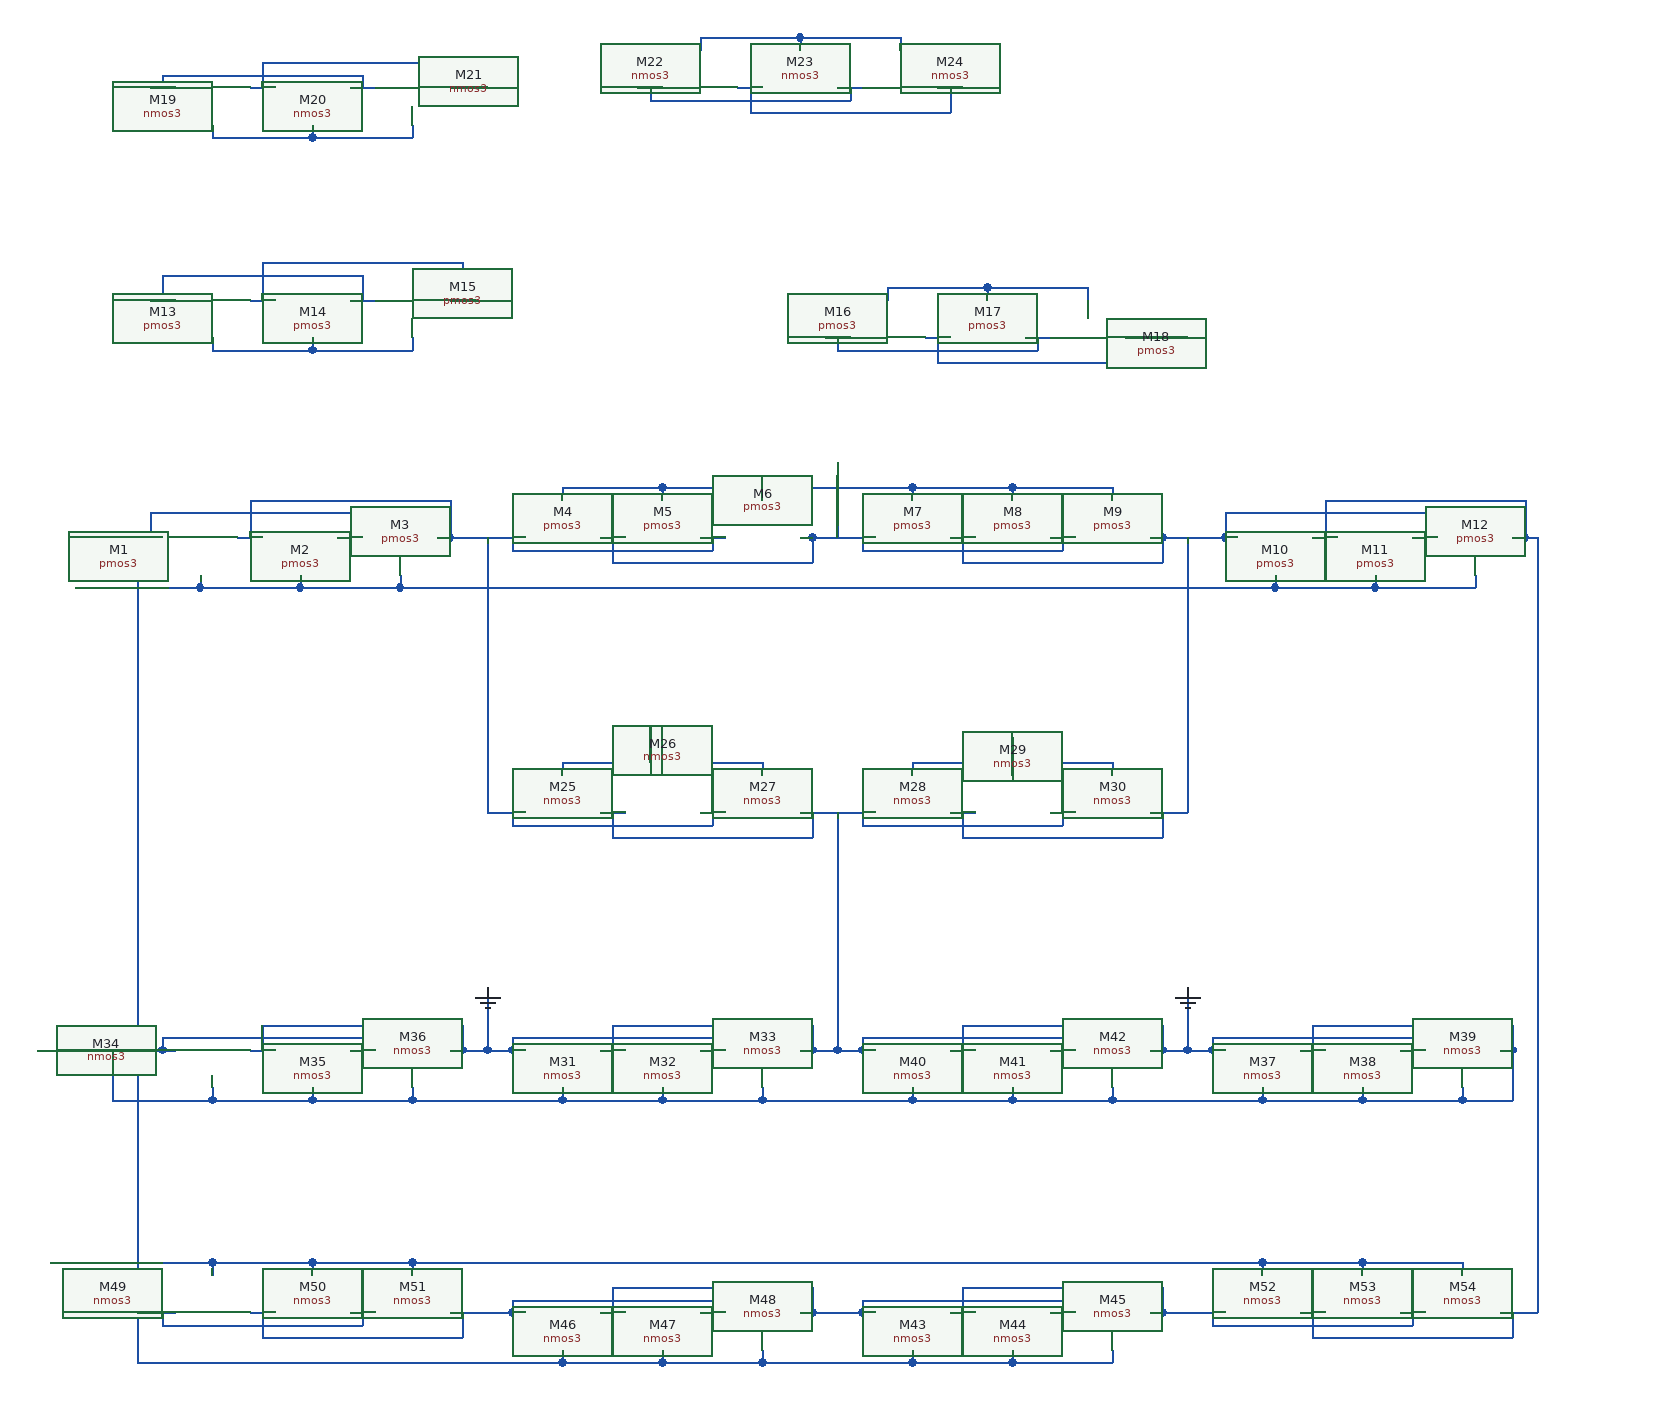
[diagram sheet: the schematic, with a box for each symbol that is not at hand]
v {xschem version=3.4.3 file_version=1.2
}
G {}
K {}
V {}
S {}
E {}
N 230 -50 230 -40 {
lab=#net1}
N 230 -40 310 -40 {
lab=#net1}
N 310 -50 310 -40 {
lab=#net1}
N 310 -40 390 -40 {
lab=#net1}
N 390 -50 390 -40 {
lab=#net1}
N 260 -80 280 -80 {
lab=#net2}
N 340 -80 360 -80 {
lab=#net3}
N 190 -80 200 -80 {
lab=#net3}
N 190 -100 190 -80 {
lab=#net3}
N 190 -100 350 -100 {
lab=#net3}
N 350 -100 350 -80 {
lab=#net3}
N 420 -80 430 -80 {
lab=#net2}
N 180 -80 190 -80 {
lab=#net3}
N 270 -110 270 -80 {
lab=#net2}
N 270 -110 420 -110 {
lab=#net2}
N 420 -110 430 -110 {
lab=#net2}
N 430 -110 430 -80 {
lab=#net2}
N 430 -80 440 -80 {
lab=#net2}
N 520 -120 520 -110 {
lab=#net4}
N 520 -120 600 -120 {
lab=#net4}
N 600 -120 600 -110 {
lab=#net4}
N 600 -120 680 -120 {
lab=#net4}
N 680 -120 680 -110 {
lab=#net4}
N 550 -80 570 -80 {
lab=#net5}
N 630 -80 650 -80 {
lab=#net2}
N 710 -80 720 -80 {
lab=#net5}
N 720 -80 730 -80 {
lab=#net5}
N 470 -80 490 -80 {
lab=#net2}
N 480 -80 480 -70 {
lab=#net2}
N 480 -70 640 -70 {
lab=#net2}
N 640 -80 640 -70 {
lab=#net2}
N 720 -80 720 -60 {
lab=#net5}
N 560 -60 720 -60 {
lab=#net5}
N 560 -80 560 -60 {
lab=#net5}
N 800 -120 800 -110 {
lab=#net4}
N 800 -120 880 -120 {
lab=#net4}
N 880 -120 880 -110 {
lab=#net4}
N 880 -120 960 -120 {
lab=#net4}
N 960 -120 960 -110 {
lab=#net4}
N 830 -80 850 -80 {
lab=#net6}
N 910 -80 930 -80 {
lab=#net5}
N 990 -80 1000 -80 {
lab=#net6}
N 1000 -80 1010 -80 {
lab=#net6}
N 750 -80 770 -80 {
lab=#net5}
N 760 -80 760 -70 {
lab=#net5}
N 760 -70 920 -70 {
lab=#net5}
N 920 -80 920 -70 {
lab=#net5}
N 1000 -80 1000 -60 {
lab=#net6}
N 840 -60 1000 -60 {
lab=#net6}
N 840 -80 840 -60 {
lab=#net6}
N 1090 -50 1090 -40 {
lab=#net1}
N 1090 -40 1170 -40 {
lab=#net1}
N 1170 -50 1170 -40 {
lab=#net1}
N 1170 -40 1250 -40 {
lab=#net1}
N 1250 -50 1250 -40 {
lab=#net1}
N 1120 -80 1140 -80 {
lab=#net7}
N 1200 -80 1220 -80 {
lab=#net6}
N 1050 -80 1060 -80 {
lab=#net6}
N 1050 -100 1050 -80 {
lab=#net6}
N 1050 -100 1210 -100 {
lab=#net6}
N 1210 -100 1210 -80 {
lab=#net6}
N 1280 -80 1290 -80 {
lab=#net7}
N 1040 -80 1050 -80 {
lab=#net6}
N 1130 -110 1130 -80 {
lab=#net7}
N 1130 -110 1280 -110 {
lab=#net7}
N 1280 -110 1290 -110 {
lab=#net7}
N 1290 -110 1290 -80 {
lab=#net7}
N 1290 -80 1300 -80 {
lab=#net7}
N 440 -80 470 -80 {
lab=#net2}
N 730 -80 750 -80 {
lab=#net5}
N 740 -140 740 -80 {
lab=#net5}
N 1010 -80 1040 -80 {
lab=#net6}
N 390 -40 1090 -40 {
lab=#net1}
N 680 -120 800 -120 {
lab=#net4}
N 240 -240 240 -230 {
lab=#net8}
N 240 -230 320 -230 {
lab=#net8}
N 320 -240 320 -230 {
lab=#net8}
N 320 -230 400 -230 {
lab=#net8}
N 400 -240 400 -230 {
lab=#net8}
N 270 -270 290 -270 {
lab=#net9}
N 350 -270 370 -270 {
lab=#net10}
N 200 -270 210 -270 {
lab=#net10}
N 200 -290 200 -270 {
lab=#net10}
N 200 -290 360 -290 {
lab=#net10}
N 360 -290 360 -270 {
lab=#net10}
N 430 -270 440 -270 {
lab=#net9}
N 190 -270 200 -270 {
lab=#net10}
N 280 -300 280 -270 {
lab=#net9}
N 280 -300 430 -300 {
lab=#net9}
N 430 -300 440 -300 {
lab=#net9}
N 440 -300 440 -270 {
lab=#net9}
N 440 -270 450 -270 {
lab=#net9}
N 780 -280 780 -270 {
lab=#net11}
N 780 -280 860 -280 {
lab=#net11}
N 860 -280 860 -270 {
lab=#net11}
N 860 -280 940 -280 {
lab=#net11}
N 940 -280 940 -270 {
lab=#net11}
N 810 -240 830 -240 {
lab=#net12}
N 890 -240 910 -240 {
lab=#net13}
N 970 -240 980 -240 {
lab=#net12}
N 980 -240 990 -240 {
lab=#net12}
N 730 -240 750 -240 {
lab=#net13}
N 740 -240 740 -230 {
lab=#net13}
N 740 -230 900 -230 {
lab=#net13}
N 900 -240 900 -230 {
lab=#net13}
N 980 -240 980 -220 {
lab=#net12}
N 820 -220 980 -220 {
lab=#net12}
N 820 -240 820 -220 {
lab=#net12}
N 990 -240 1020 -240 {
lab=#net12}
N 130 -40 230 -40 {
lab=#net1}
N 240 -410 240 -400 {
lab=#net14}
N 240 -400 320 -400 {
lab=#net14}
N 320 -410 320 -400 {
lab=#net14}
N 320 -400 400 -400 {
lab=#net14}
N 400 -410 400 -400 {
lab=#net14}
N 200 -440 210 -440 {
lab=#net15}
N 270 -440 290 -440 {
lab=#net16}
N 350 -440 370 -440 {
lab=#net15}
N 430 -440 440 -440 {
lab=#net16}
N 440 -440 460 -440 {
lab=#net16}
N 190 -440 200 -440 {
lab=#net15}
N 360 -450 360 -440 {
lab=#net15}
N 200 -450 360 -450 {
lab=#net15}
N 200 -450 200 -440 {
lab=#net15}
N 280 -460 280 -440 {
lab=#net16}
N 280 -460 440 -460 {
lab=#net16}
N 440 -460 440 -440 {
lab=#net16}
N 660 -440 680 -440 {
lab=#net17}
N 740 -440 760 -440 {
lab=#net18}
N 630 -480 630 -470 {
lab=#net19}
N 630 -480 710 -480 {
lab=#net19}
N 710 -480 710 -470 {
lab=#net19}
N 710 -480 790 -480 {
lab=#net19}
N 790 -480 790 -470 {
lab=#net19}
N 580 -440 600 -440 {
lab=#net18}
N 820 -440 840 -440 {
lab=#net17}
N 590 -440 590 -430 {
lab=#net18}
N 590 -430 750 -430 {
lab=#net18}
N 750 -440 750 -430 {
lab=#net18}
N 670 -440 670 -420 {
lab=#net17}
N 670 -420 830 -420 {
lab=#net17}
N 830 -440 830 -420 {
lab=#net17}
N 830 140 850 140 {
lab=#net6}
N 910 140 930 140 {
lab=#net20}
N 800 100 800 110 {
lab=#net21}
N 800 100 880 100 {
lab=#net21}
N 880 100 880 110 {
lab=#net21}
N 880 100 960 100 {
lab=#net21}
N 960 100 960 110 {
lab=#net21}
N 750 140 770 140 {
lab=#net20}
N 990 140 1010 140 {
lab=#net6}
N 760 140 760 150 {
lab=#net20}
N 760 150 920 150 {
lab=#net20}
N 920 140 920 150 {
lab=#net20}
N 840 140 840 160 {
lab=#net6}
N 840 160 1000 160 {
lab=#net6}
N 1000 140 1000 160 {
lab=#net6}
N 550 140 570 140 {
lab=#net20}
N 630 140 650 140 {
lab=#net2}
N 520 100 520 110 {
lab=#net22}
N 520 100 600 100 {
lab=#net22}
N 600 100 600 110 {
lab=#net22}
N 600 100 680 100 {
lab=#net22}
N 680 100 680 110 {
lab=#net22}
N 470 140 490 140 {
lab=#net2}
N 710 140 730 140 {
lab=#net20}
N 480 140 480 150 {
lab=#net2}
N 480 150 640 150 {
lab=#net2}
N 640 140 640 150 {
lab=#net2}
N 560 140 560 160 {
lab=#net20}
N 560 160 720 160 {
lab=#net20}
N 720 140 720 160 {
lab=#net20}
N 460 -80 460 140 {
lab=#net2}
N 1010 140 1020 140 {
lab=#net6}
N 1020 -80 1020 140 {
lab=#net6}
N 590 70 590 100 {
lab=#net22}
N 880 80 880 90 {
lab=#net21}
N 880 90 880 100 {
lab=#net21}
N 730 140 750 140 {
lab=#net20}
N 740 140 740 240 {
lab=#net20}
N 460 140 470 140 {
lab=#net2}
N 520 360 520 370 {
lab=#net23}
N 520 370 600 370 {
lab=#net23}
N 600 360 600 370 {
lab=#net23}
N 600 370 680 370 {
lab=#net23}
N 680 360 680 370 {
lab=#net23}
N 480 330 490 330 {
lab=GND}
N 550 330 570 330 {
lab=#net20}
N 630 330 650 330 {
lab=GND}
N 710 330 720 330 {
lab=#net20}
N 720 330 740 330 {
lab=#net20}
N 470 330 480 330 {
lab=GND}
N 640 320 640 330 {
lab=GND}
N 480 320 640 320 {
lab=GND}
N 480 320 480 330 {
lab=GND}
N 560 310 560 330 {
lab=#net20}
N 560 310 720 310 {
lab=#net20}
N 720 310 720 330 {
lab=#net20}
N 240 360 240 370 {
lab=#net23}
N 240 370 320 370 {
lab=#net23}
N 320 360 320 370 {
lab=#net23}
N 320 370 400 370 {
lab=#net23}
N 400 360 400 370 {
lab=#net23}
N 200 330 210 330 {
lab=#net23}
N 270 330 290 330 {
lab=GND}
N 350 330 370 330 {
lab=#net23}
N 430 330 440 330 {
lab=GND}
N 440 330 460 330 {
lab=GND}
N 190 330 200 330 {
lab=#net23}
N 360 320 360 330 {
lab=#net23}
N 200 320 360 320 {
lab=#net23}
N 200 320 200 330 {
lab=#net23}
N 280 310 280 330 {
lab=GND}
N 280 310 440 310 {
lab=GND}
N 440 310 440 330 {
lab=GND}
N 400 370 520 370 {
lab=#net23}
N 460 330 470 330 {
lab=GND}
N 460 280 460 330 {
lab=GND}
N 740 240 740 330 {
lab=#net20}
N 1080 360 1080 370 {
lab=#net23}
N 1080 370 1160 370 {
lab=#net23}
N 1160 360 1160 370 {
lab=#net23}
N 1160 370 1240 370 {
lab=#net23}
N 1240 360 1240 370 {
lab=#net23}
N 1040 330 1050 330 {
lab=GND}
N 1110 330 1130 330 {
lab=#net23}
N 1190 330 1210 330 {
lab=GND}
N 1270 330 1280 330 {
lab=#net23}
N 1030 330 1040 330 {
lab=GND}
N 1200 320 1200 330 {
lab=GND}
N 1040 320 1200 320 {
lab=GND}
N 1040 320 1040 330 {
lab=GND}
N 1120 310 1120 330 {
lab=#net23}
N 1120 310 1280 310 {
lab=#net23}
N 1280 310 1280 330 {
lab=#net23}
N 800 360 800 370 {
lab=#net23}
N 800 370 880 370 {
lab=#net23}
N 880 360 880 370 {
lab=#net23}
N 880 370 960 370 {
lab=#net23}
N 960 360 960 370 {
lab=#net23}
N 760 330 770 330 {
lab=#net20}
N 830 330 850 330 {
lab=GND}
N 910 330 930 330 {
lab=#net20}
N 990 330 1000 330 {
lab=GND}
N 1000 330 1020 330 {
lab=GND}
N 750 330 760 330 {
lab=#net20}
N 920 320 920 330 {
lab=#net20}
N 760 320 920 320 {
lab=#net20}
N 760 320 760 330 {
lab=#net20}
N 840 310 840 330 {
lab=GND}
N 840 310 1000 310 {
lab=GND}
N 1000 310 1000 330 {
lab=GND}
N 960 370 1080 370 {
lab=#net23}
N 1020 330 1030 330 {
lab=GND}
N 1020 280 1020 330 {
lab=GND}
N 740 330 750 330 {
lab=#net20}
N 100 330 190 330 {
lab=#net23}
N 160 370 240 370 {
lab=#net23}
N 160 330 160 370 {
lab=#net23}
N 680 370 800 370 {
lab=#net23}
N 1240 370 1280 370 {
lab=#net23}
N 1280 330 1280 370 {
lab=#net23}
N 800 570 800 580 {
lab=#net3}
N 800 580 880 580 {
lab=#net3}
N 880 570 880 580 {
lab=#net3}
N 880 580 960 580 {
lab=#net3}
N 960 570 960 580 {
lab=#net3}
N 760 540 770 540 {
lab=#net24}
N 830 540 850 540 {
lab=#net25}
N 910 540 930 540 {
lab=#net24}
N 990 540 1000 540 {
lab=#net25}
N 1000 540 1020 540 {
lab=#net25}
N 750 540 760 540 {
lab=#net24}
N 920 530 920 540 {
lab=#net24}
N 760 530 920 530 {
lab=#net24}
N 760 530 760 540 {
lab=#net24}
N 840 520 840 540 {
lab=#net25}
N 840 520 1000 520 {
lab=#net25}
N 1000 520 1000 540 {
lab=#net25}
N 520 570 520 580 {
lab=#net3}
N 520 580 600 580 {
lab=#net3}
N 600 570 600 580 {
lab=#net3}
N 600 580 680 580 {
lab=#net3}
N 680 570 680 580 {
lab=#net3}
N 480 540 490 540 {
lab=#net26}
N 550 540 570 540 {
lab=#net24}
N 630 540 650 540 {
lab=#net26}
N 710 540 720 540 {
lab=#net24}
N 720 540 740 540 {
lab=#net24}
N 470 540 480 540 {
lab=#net26}
N 640 530 640 540 {
lab=#net26}
N 480 530 640 530 {
lab=#net26}
N 480 530 480 540 {
lab=#net26}
N 560 520 560 540 {
lab=#net24}
N 560 520 720 520 {
lab=#net24}
N 720 520 720 540 {
lab=#net24}
N 740 540 750 540 {
lab=#net24}
N 270 540 290 540 {
lab=#net26}
N 350 540 370 540 {
lab=#net3}
N 240 500 240 510 {
lab=#net27}
N 240 500 320 500 {
lab=#net27}
N 320 500 320 510 {
lab=#net27}
N 320 500 400 500 {
lab=#net27}
N 400 500 400 510 {
lab=#net27}
N 190 540 210 540 {
lab=#net3}
N 430 540 450 540 {
lab=#net26}
N 200 540 200 550 {
lab=#net3}
N 200 550 360 550 {
lab=#net3}
N 360 540 360 550 {
lab=#net3}
N 280 540 280 560 {
lab=#net26}
N 280 560 440 560 {
lab=#net26}
N 440 540 440 560 {
lab=#net26}
N 1110 540 1130 540 {
lab=#net7}
N 1190 540 1210 540 {
lab=#net25}
N 1080 500 1080 510 {
lab=#net27}
N 1080 500 1160 500 {
lab=#net27}
N 1160 500 1160 510 {
lab=#net27}
N 1160 500 1240 500 {
lab=#net27}
N 1240 500 1240 510 {
lab=#net27}
N 1030 540 1050 540 {
lab=#net25}
N 1270 540 1290 540 {
lab=#net7}
N 1040 540 1040 550 {
lab=#net25}
N 1040 550 1200 550 {
lab=#net25}
N 1200 540 1200 550 {
lab=#net25}
N 1120 540 1120 560 {
lab=#net7}
N 1120 560 1280 560 {
lab=#net7}
N 1280 540 1280 560 {
lab=#net7}
N 1020 540 1030 540 {
lab=#net25}
N 450 540 470 540 {
lab=#net26}
N 400 500 1080 500 {
lab=#net27}
N 110 500 240 500 {
lab=#net27}
N 680 580 800 580 {
lab=#net3}
N 180 580 520 580 {
lab=#net3}
N 180 -80 180 580 {
lab=#net3}
N 180 540 190 540 {
lab=#net3}
N 1290 540 1300 540 {
lab=#net7}
N 1300 -80 1300 540 {
lab=#net7}
C {madvlsi/pmos3.sym} 230 -80 3 0 {name=M1
L=0.5
W=4
body=VDD
nf=1
mult=1
ad="'int((nf+1)/2) * W/nf * 0.29'" 
pd="'2*int((nf+1)/2) * (W/nf + 0.29)'"
as="'int((nf+2)/2) * W/nf * 0.29'" 
ps="'2*int((nf+2)/2) * (W/nf + 0.29)'"
nrd="'0.29 / W'" nrs="'0.29 / W'"
sa=0 sb=0 sd=0
model=pfet_01v8
spiceprefix=X
}
C {madvlsi/pmos3.sym} 310 -80 3 0 {name=M2
L=0.5
W=4
body=VDD
nf=1
mult=1
ad="'int((nf+1)/2) * W/nf * 0.29'" 
pd="'2*int((nf+1)/2) * (W/nf + 0.29)'"
as="'int((nf+2)/2) * W/nf * 0.29'" 
ps="'2*int((nf+2)/2) * (W/nf + 0.29)'"
nrd="'0.29 / W'" nrs="'0.29 / W'"
sa=0 sb=0 sd=0
model=pfet_01v8
spiceprefix=X
}
C {madvlsi/pmos3.sym} 390 -80 3 0 {name=M3
L=0.5
W=4
body=VDD
nf=1
mult=1
ad="'int((nf+1)/2) * W/nf * 0.29'" 
pd="'2*int((nf+1)/2) * (W/nf + 0.29)'"
as="'int((nf+2)/2) * W/nf * 0.29'" 
ps="'2*int((nf+2)/2) * (W/nf + 0.29)'"
nrd="'0.29 / W'" nrs="'0.29 / W'"
sa=0 sb=0 sd=0
model=pfet_01v8
spiceprefix=X
}
C {madvlsi/pmos3.sym} 520 -80 1 0 {name=M4
L=0.5
W=4
body=VDD
nf=1
mult=1
ad="'int((nf+1)/2) * W/nf * 0.29'" 
pd="'2*int((nf+1)/2) * (W/nf + 0.29)'"
as="'int((nf+2)/2) * W/nf * 0.29'" 
ps="'2*int((nf+2)/2) * (W/nf + 0.29)'"
nrd="'0.29 / W'" nrs="'0.29 / W'"
sa=0 sb=0 sd=0
model=pfet_01v8
spiceprefix=X
}
C {madvlsi/pmos3.sym} 600 -80 1 0 {name=M5
L=0.5
W=4
body=VDD
nf=1
mult=1
ad="'int((nf+1)/2) * W/nf * 0.29'" 
pd="'2*int((nf+1)/2) * (W/nf + 0.29)'"
as="'int((nf+2)/2) * W/nf * 0.29'" 
ps="'2*int((nf+2)/2) * (W/nf + 0.29)'"
nrd="'0.29 / W'" nrs="'0.29 / W'"
sa=0 sb=0 sd=0
model=pfet_01v8
spiceprefix=X
}
C {madvlsi/pmos3.sym} 680 -80 1 0 {name=M6
L=0.5
W=4
body=VDD
nf=1
mult=1
ad="'int((nf+1)/2) * W/nf * 0.29'" 
pd="'2*int((nf+1)/2) * (W/nf + 0.29)'"
as="'int((nf+2)/2) * W/nf * 0.29'" 
ps="'2*int((nf+2)/2) * (W/nf + 0.29)'"
nrd="'0.29 / W'" nrs="'0.29 / W'"
sa=0 sb=0 sd=0
model=pfet_01v8
spiceprefix=X
}
C {madvlsi/pmos3.sym} 800 -80 1 0 {name=M7
L=0.5
W=4
body=VDD
nf=1
mult=1
ad="'int((nf+1)/2) * W/nf * 0.29'" 
pd="'2*int((nf+1)/2) * (W/nf + 0.29)'"
as="'int((nf+2)/2) * W/nf * 0.29'" 
ps="'2*int((nf+2)/2) * (W/nf + 0.29)'"
nrd="'0.29 / W'" nrs="'0.29 / W'"
sa=0 sb=0 sd=0
model=pfet_01v8
spiceprefix=X
}
C {madvlsi/pmos3.sym} 880 -80 1 0 {name=M8
L=0.5
W=4
body=VDD
nf=1
mult=1
ad="'int((nf+1)/2) * W/nf * 0.29'" 
pd="'2*int((nf+1)/2) * (W/nf + 0.29)'"
as="'int((nf+2)/2) * W/nf * 0.29'" 
ps="'2*int((nf+2)/2) * (W/nf + 0.29)'"
nrd="'0.29 / W'" nrs="'0.29 / W'"
sa=0 sb=0 sd=0
model=pfet_01v8
spiceprefix=X
}
C {madvlsi/pmos3.sym} 960 -80 1 0 {name=M9
L=0.5
W=4
body=VDD
nf=1
mult=1
ad="'int((nf+1)/2) * W/nf * 0.29'" 
pd="'2*int((nf+1)/2) * (W/nf + 0.29)'"
as="'int((nf+2)/2) * W/nf * 0.29'" 
ps="'2*int((nf+2)/2) * (W/nf + 0.29)'"
nrd="'0.29 / W'" nrs="'0.29 / W'"
sa=0 sb=0 sd=0
model=pfet_01v8
spiceprefix=X
}
C {madvlsi/pmos3.sym} 1090 -80 3 0 {name=M10
L=0.5
W=4
body=VDD
nf=1
mult=1
ad="'int((nf+1)/2) * W/nf * 0.29'" 
pd="'2*int((nf+1)/2) * (W/nf + 0.29)'"
as="'int((nf+2)/2) * W/nf * 0.29'" 
ps="'2*int((nf+2)/2) * (W/nf + 0.29)'"
nrd="'0.29 / W'" nrs="'0.29 / W'"
sa=0 sb=0 sd=0
model=pfet_01v8
spiceprefix=X
}
C {madvlsi/pmos3.sym} 1170 -80 3 0 {name=M11
L=0.5
W=4
body=VDD
nf=1
mult=1
ad="'int((nf+1)/2) * W/nf * 0.29'" 
pd="'2*int((nf+1)/2) * (W/nf + 0.29)'"
as="'int((nf+2)/2) * W/nf * 0.29'" 
ps="'2*int((nf+2)/2) * (W/nf + 0.29)'"
nrd="'0.29 / W'" nrs="'0.29 / W'"
sa=0 sb=0 sd=0
model=pfet_01v8
spiceprefix=X
}
C {madvlsi/pmos3.sym} 1250 -80 3 0 {name=M12
L=0.5
W=4
body=VDD
nf=1
mult=1
ad="'int((nf+1)/2) * W/nf * 0.29'" 
pd="'2*int((nf+1)/2) * (W/nf + 0.29)'"
as="'int((nf+2)/2) * W/nf * 0.29'" 
ps="'2*int((nf+2)/2) * (W/nf + 0.29)'"
nrd="'0.29 / W'" nrs="'0.29 / W'"
sa=0 sb=0 sd=0
model=pfet_01v8
spiceprefix=X
}
C {madvlsi/pmos3.sym} 240 -270 3 0 {name=M13
L=0.5
W=4
body=VDD
nf=1
mult=1
ad="'int((nf+1)/2) * W/nf * 0.29'" 
pd="'2*int((nf+1)/2) * (W/nf + 0.29)'"
as="'int((nf+2)/2) * W/nf * 0.29'" 
ps="'2*int((nf+2)/2) * (W/nf + 0.29)'"
nrd="'0.29 / W'" nrs="'0.29 / W'"
sa=0 sb=0 sd=0
model=pfet_01v8
spiceprefix=X
}
C {madvlsi/pmos3.sym} 320 -270 3 0 {name=M14
L=0.5
W=4
body=VDD
nf=1
mult=1
ad="'int((nf+1)/2) * W/nf * 0.29'" 
pd="'2*int((nf+1)/2) * (W/nf + 0.29)'"
as="'int((nf+2)/2) * W/nf * 0.29'" 
ps="'2*int((nf+2)/2) * (W/nf + 0.29)'"
nrd="'0.29 / W'" nrs="'0.29 / W'"
sa=0 sb=0 sd=0
model=pfet_01v8
spiceprefix=X
}
C {madvlsi/pmos3.sym} 400 -270 3 0 {name=M15
L=0.5
W=4
body=VDD
nf=1
mult=1
ad="'int((nf+1)/2) * W/nf * 0.29'" 
pd="'2*int((nf+1)/2) * (W/nf + 0.29)'"
as="'int((nf+2)/2) * W/nf * 0.29'" 
ps="'2*int((nf+2)/2) * (W/nf + 0.29)'"
nrd="'0.29 / W'" nrs="'0.29 / W'"
sa=0 sb=0 sd=0
model=pfet_01v8
spiceprefix=X
}
C {madvlsi/pmos3.sym} 780 -240 1 0 {name=M16
L=0.5
W=4
body=VDD
nf=1
mult=1
ad="'int((nf+1)/2) * W/nf * 0.29'" 
pd="'2*int((nf+1)/2) * (W/nf + 0.29)'"
as="'int((nf+2)/2) * W/nf * 0.29'" 
ps="'2*int((nf+2)/2) * (W/nf + 0.29)'"
nrd="'0.29 / W'" nrs="'0.29 / W'"
sa=0 sb=0 sd=0
model=pfet_01v8
spiceprefix=X
}
C {madvlsi/pmos3.sym} 860 -240 1 0 {name=M17
L=0.5
W=4
body=VDD
nf=1
mult=1
ad="'int((nf+1)/2) * W/nf * 0.29'" 
pd="'2*int((nf+1)/2) * (W/nf + 0.29)'"
as="'int((nf+2)/2) * W/nf * 0.29'" 
ps="'2*int((nf+2)/2) * (W/nf + 0.29)'"
nrd="'0.29 / W'" nrs="'0.29 / W'"
sa=0 sb=0 sd=0
model=pfet_01v8
spiceprefix=X
}
C {madvlsi/pmos3.sym} 940 -240 1 0 {name=M18
L=0.5
W=4
body=VDD
nf=1
mult=1
ad="'int((nf+1)/2) * W/nf * 0.29'" 
pd="'2*int((nf+1)/2) * (W/nf + 0.29)'"
as="'int((nf+2)/2) * W/nf * 0.29'" 
ps="'2*int((nf+2)/2) * (W/nf + 0.29)'"
nrd="'0.29 / W'" nrs="'0.29 / W'"
sa=0 sb=0 sd=0
model=pfet_01v8
spiceprefix=X
}
C {madvlsi/nmos3.sym} 240 -440 3 0 {name=M19
L=0.5
W=4
body=GND
nf=1
mult=1
ad="'int((nf+1)/2) * W/nf * 0.29'" 
pd="'2*int((nf+1)/2) * (W/nf + 0.29)'"
as="'int((nf+2)/2) * W/nf * 0.29'" 
ps="'2*int((nf+2)/2) * (W/nf + 0.29)'"
nrd="'0.29 / W'" nrs="'0.29 / W'"
sa=0 sb=0 sd=0
model=nfet_01v8
spiceprefix=X
}
C {madvlsi/nmos3.sym} 320 -440 3 0 {name=M20
L=0.5
W=4
body=GND
nf=1
mult=1
ad="'int((nf+1)/2) * W/nf * 0.29'" 
pd="'2*int((nf+1)/2) * (W/nf + 0.29)'"
as="'int((nf+2)/2) * W/nf * 0.29'" 
ps="'2*int((nf+2)/2) * (W/nf + 0.29)'"
nrd="'0.29 / W'" nrs="'0.29 / W'"
sa=0 sb=0 sd=0
model=nfet_01v8
spiceprefix=X
}
C {madvlsi/nmos3.sym} 400 -440 3 0 {name=M21
L=0.5
W=4
body=GND
nf=1
mult=1
ad="'int((nf+1)/2) * W/nf * 0.29'" 
pd="'2*int((nf+1)/2) * (W/nf + 0.29)'"
as="'int((nf+2)/2) * W/nf * 0.29'" 
ps="'2*int((nf+2)/2) * (W/nf + 0.29)'"
nrd="'0.29 / W'" nrs="'0.29 / W'"
sa=0 sb=0 sd=0
model=nfet_01v8
spiceprefix=X
}
C {madvlsi/nmos3.sym} 630 -440 1 0 {name=M22
L=0.5
W=4
body=GND
nf=1
mult=1
ad="'int((nf+1)/2) * W/nf * 0.29'" 
pd="'2*int((nf+1)/2) * (W/nf + 0.29)'"
as="'int((nf+2)/2) * W/nf * 0.29'" 
ps="'2*int((nf+2)/2) * (W/nf + 0.29)'"
nrd="'0.29 / W'" nrs="'0.29 / W'"
sa=0 sb=0 sd=0
model=nfet_01v8
spiceprefix=X
}
C {madvlsi/nmos3.sym} 710 -440 1 0 {name=M23
L=0.5
W=4
body=GND
nf=1
mult=1
ad="'int((nf+1)/2) * W/nf * 0.29'" 
pd="'2*int((nf+1)/2) * (W/nf + 0.29)'"
as="'int((nf+2)/2) * W/nf * 0.29'" 
ps="'2*int((nf+2)/2) * (W/nf + 0.29)'"
nrd="'0.29 / W'" nrs="'0.29 / W'"
sa=0 sb=0 sd=0
model=nfet_01v8
spiceprefix=X
}
C {madvlsi/nmos3.sym} 790 -440 1 0 {name=M24
L=0.5
W=4
body=GND
nf=1
mult=1
ad="'int((nf+1)/2) * W/nf * 0.29'" 
pd="'2*int((nf+1)/2) * (W/nf + 0.29)'"
as="'int((nf+2)/2) * W/nf * 0.29'" 
ps="'2*int((nf+2)/2) * (W/nf + 0.29)'"
nrd="'0.29 / W'" nrs="'0.29 / W'"
sa=0 sb=0 sd=0
model=nfet_01v8
spiceprefix=X
}
C {madvlsi/nmos3.sym} 800 140 1 0 {name=M28
L=0.5
W=4
body=GND
nf=1
mult=1
ad="'int((nf+1)/2) * W/nf * 0.29'" 
pd="'2*int((nf+1)/2) * (W/nf + 0.29)'"
as="'int((nf+2)/2) * W/nf * 0.29'" 
ps="'2*int((nf+2)/2) * (W/nf + 0.29)'"
nrd="'0.29 / W'" nrs="'0.29 / W'"
sa=0 sb=0 sd=0
model=nfet_01v8
spiceprefix=X
}
C {madvlsi/nmos3.sym} 880 140 1 0 {name=M29
L=0.5
W=4
body=GND
nf=1
mult=1
ad="'int((nf+1)/2) * W/nf * 0.29'" 
pd="'2*int((nf+1)/2) * (W/nf + 0.29)'"
as="'int((nf+2)/2) * W/nf * 0.29'" 
ps="'2*int((nf+2)/2) * (W/nf + 0.29)'"
nrd="'0.29 / W'" nrs="'0.29 / W'"
sa=0 sb=0 sd=0
model=nfet_01v8
spiceprefix=X
}
C {madvlsi/nmos3.sym} 960 140 1 0 {name=M30
L=0.5
W=4
body=GND
nf=1
mult=1
ad="'int((nf+1)/2) * W/nf * 0.29'" 
pd="'2*int((nf+1)/2) * (W/nf + 0.29)'"
as="'int((nf+2)/2) * W/nf * 0.29'" 
ps="'2*int((nf+2)/2) * (W/nf + 0.29)'"
nrd="'0.29 / W'" nrs="'0.29 / W'"
sa=0 sb=0 sd=0
model=nfet_01v8
spiceprefix=X
}
C {madvlsi/nmos3.sym} 520 140 1 0 {name=M25
L=0.5
W=4
body=GND
nf=1
mult=1
ad="'int((nf+1)/2) * W/nf * 0.29'" 
pd="'2*int((nf+1)/2) * (W/nf + 0.29)'"
as="'int((nf+2)/2) * W/nf * 0.29'" 
ps="'2*int((nf+2)/2) * (W/nf + 0.29)'"
nrd="'0.29 / W'" nrs="'0.29 / W'"
sa=0 sb=0 sd=0
model=nfet_01v8
spiceprefix=X
}
C {madvlsi/nmos3.sym} 600 140 1 0 {name=M26
L=0.5
W=4
body=GND
nf=1
mult=1
ad="'int((nf+1)/2) * W/nf * 0.29'" 
pd="'2*int((nf+1)/2) * (W/nf + 0.29)'"
as="'int((nf+2)/2) * W/nf * 0.29'" 
ps="'2*int((nf+2)/2) * (W/nf + 0.29)'"
nrd="'0.29 / W'" nrs="'0.29 / W'"
sa=0 sb=0 sd=0
model=nfet_01v8
spiceprefix=X
}
C {madvlsi/nmos3.sym} 680 140 1 0 {name=M27
L=0.5
W=4
body=GND
nf=1
mult=1
ad="'int((nf+1)/2) * W/nf * 0.29'" 
pd="'2*int((nf+1)/2) * (W/nf + 0.29)'"
as="'int((nf+2)/2) * W/nf * 0.29'" 
ps="'2*int((nf+2)/2) * (W/nf + 0.29)'"
nrd="'0.29 / W'" nrs="'0.29 / W'"
sa=0 sb=0 sd=0
model=nfet_01v8
spiceprefix=X
}
C {madvlsi/nmos3.sym} 520 330 3 0 {name=M31
L=0.5
W=4
body=GND
nf=1
mult=1
ad="'int((nf+1)/2) * W/nf * 0.29'" 
pd="'2*int((nf+1)/2) * (W/nf + 0.29)'"
as="'int((nf+2)/2) * W/nf * 0.29'" 
ps="'2*int((nf+2)/2) * (W/nf + 0.29)'"
nrd="'0.29 / W'" nrs="'0.29 / W'"
sa=0 sb=0 sd=0
model=nfet_01v8
spiceprefix=X
}
C {madvlsi/nmos3.sym} 600 330 3 0 {name=M32
L=0.5
W=4
body=GND
nf=1
mult=1
ad="'int((nf+1)/2) * W/nf * 0.29'" 
pd="'2*int((nf+1)/2) * (W/nf + 0.29)'"
as="'int((nf+2)/2) * W/nf * 0.29'" 
ps="'2*int((nf+2)/2) * (W/nf + 0.29)'"
nrd="'0.29 / W'" nrs="'0.29 / W'"
sa=0 sb=0 sd=0
model=nfet_01v8
spiceprefix=X
}
C {madvlsi/nmos3.sym} 680 330 3 0 {name=M33
L=0.5
W=4
body=GND
nf=1
mult=1
ad="'int((nf+1)/2) * W/nf * 0.29'" 
pd="'2*int((nf+1)/2) * (W/nf + 0.29)'"
as="'int((nf+2)/2) * W/nf * 0.29'" 
ps="'2*int((nf+2)/2) * (W/nf + 0.29)'"
nrd="'0.29 / W'" nrs="'0.29 / W'"
sa=0 sb=0 sd=0
model=nfet_01v8
spiceprefix=X
}
C {madvlsi/nmos3.sym} 240 330 3 0 {name=M34
L=0.5
W=4
body=GND
nf=1
mult=1
ad="'int((nf+1)/2) * W/nf * 0.29'" 
pd="'2*int((nf+1)/2) * (W/nf + 0.29)'"
as="'int((nf+2)/2) * W/nf * 0.29'" 
ps="'2*int((nf+2)/2) * (W/nf + 0.29)'"
nrd="'0.29 / W'" nrs="'0.29 / W'"
sa=0 sb=0 sd=0
model=nfet_01v8
spiceprefix=X
}
C {madvlsi/nmos3.sym} 320 330 3 0 {name=M35
L=0.5
W=4
body=GND
nf=1
mult=1
ad="'int((nf+1)/2) * W/nf * 0.29'" 
pd="'2*int((nf+1)/2) * (W/nf + 0.29)'"
as="'int((nf+2)/2) * W/nf * 0.29'" 
ps="'2*int((nf+2)/2) * (W/nf + 0.29)'"
nrd="'0.29 / W'" nrs="'0.29 / W'"
sa=0 sb=0 sd=0
model=nfet_01v8
spiceprefix=X
}
C {madvlsi/nmos3.sym} 400 330 3 0 {name=M36
L=0.5
W=4
body=GND
nf=1
mult=1
ad="'int((nf+1)/2) * W/nf * 0.29'" 
pd="'2*int((nf+1)/2) * (W/nf + 0.29)'"
as="'int((nf+2)/2) * W/nf * 0.29'" 
ps="'2*int((nf+2)/2) * (W/nf + 0.29)'"
nrd="'0.29 / W'" nrs="'0.29 / W'"
sa=0 sb=0 sd=0
model=nfet_01v8
spiceprefix=X
}
C {madvlsi/gnd.sym} 460 280 2 0 {name=l1 lab=GND}
C {madvlsi/nmos3.sym} 1080 330 3 0 {name=M37
L=0.5
W=4
body=GND
nf=1
mult=1
ad="'int((nf+1)/2) * W/nf * 0.29'" 
pd="'2*int((nf+1)/2) * (W/nf + 0.29)'"
as="'int((nf+2)/2) * W/nf * 0.29'" 
ps="'2*int((nf+2)/2) * (W/nf + 0.29)'"
nrd="'0.29 / W'" nrs="'0.29 / W'"
sa=0 sb=0 sd=0
model=nfet_01v8
spiceprefix=X
}
C {madvlsi/nmos3.sym} 1160 330 3 0 {name=M38
L=0.5
W=4
body=GND
nf=1
mult=1
ad="'int((nf+1)/2) * W/nf * 0.29'" 
pd="'2*int((nf+1)/2) * (W/nf + 0.29)'"
as="'int((nf+2)/2) * W/nf * 0.29'" 
ps="'2*int((nf+2)/2) * (W/nf + 0.29)'"
nrd="'0.29 / W'" nrs="'0.29 / W'"
sa=0 sb=0 sd=0
model=nfet_01v8
spiceprefix=X
}
C {madvlsi/nmos3.sym} 1240 330 3 0 {name=M39
L=0.5
W=4
body=GND
nf=1
mult=1
ad="'int((nf+1)/2) * W/nf * 0.29'" 
pd="'2*int((nf+1)/2) * (W/nf + 0.29)'"
as="'int((nf+2)/2) * W/nf * 0.29'" 
ps="'2*int((nf+2)/2) * (W/nf + 0.29)'"
nrd="'0.29 / W'" nrs="'0.29 / W'"
sa=0 sb=0 sd=0
model=nfet_01v8
spiceprefix=X
}
C {madvlsi/nmos3.sym} 800 330 3 0 {name=M40
L=0.5
W=4
body=GND
nf=1
mult=1
ad="'int((nf+1)/2) * W/nf * 0.29'" 
pd="'2*int((nf+1)/2) * (W/nf + 0.29)'"
as="'int((nf+2)/2) * W/nf * 0.29'" 
ps="'2*int((nf+2)/2) * (W/nf + 0.29)'"
nrd="'0.29 / W'" nrs="'0.29 / W'"
sa=0 sb=0 sd=0
model=nfet_01v8
spiceprefix=X
}
C {madvlsi/nmos3.sym} 880 330 3 0 {name=M41
L=0.5
W=4
body=GND
nf=1
mult=1
ad="'int((nf+1)/2) * W/nf * 0.29'" 
pd="'2*int((nf+1)/2) * (W/nf + 0.29)'"
as="'int((nf+2)/2) * W/nf * 0.29'" 
ps="'2*int((nf+2)/2) * (W/nf + 0.29)'"
nrd="'0.29 / W'" nrs="'0.29 / W'"
sa=0 sb=0 sd=0
model=nfet_01v8
spiceprefix=X
}
C {madvlsi/nmos3.sym} 960 330 3 0 {name=M42
L=0.5
W=4
body=GND
nf=1
mult=1
ad="'int((nf+1)/2) * W/nf * 0.29'" 
pd="'2*int((nf+1)/2) * (W/nf + 0.29)'"
as="'int((nf+2)/2) * W/nf * 0.29'" 
ps="'2*int((nf+2)/2) * (W/nf + 0.29)'"
nrd="'0.29 / W'" nrs="'0.29 / W'"
sa=0 sb=0 sd=0
model=nfet_01v8
spiceprefix=X
}
C {madvlsi/gnd.sym} 1020 280 2 0 {name=l2 lab=GND}
C {madvlsi/nmos3.sym} 800 540 3 0 {name=M43
L=0.5
W=4
body=GND
nf=1
mult=1
ad="'int((nf+1)/2) * W/nf * 0.29'" 
pd="'2*int((nf+1)/2) * (W/nf + 0.29)'"
as="'int((nf+2)/2) * W/nf * 0.29'" 
ps="'2*int((nf+2)/2) * (W/nf + 0.29)'"
nrd="'0.29 / W'" nrs="'0.29 / W'"
sa=0 sb=0 sd=0
model=nfet_01v8
spiceprefix=X
}
C {madvlsi/nmos3.sym} 880 540 3 0 {name=M44
L=0.5
W=4
body=GND
nf=1
mult=1
ad="'int((nf+1)/2) * W/nf * 0.29'" 
pd="'2*int((nf+1)/2) * (W/nf + 0.29)'"
as="'int((nf+2)/2) * W/nf * 0.29'" 
ps="'2*int((nf+2)/2) * (W/nf + 0.29)'"
nrd="'0.29 / W'" nrs="'0.29 / W'"
sa=0 sb=0 sd=0
model=nfet_01v8
spiceprefix=X
}
C {madvlsi/nmos3.sym} 960 540 3 0 {name=M45
L=0.5
W=4
body=GND
nf=1
mult=1
ad="'int((nf+1)/2) * W/nf * 0.29'" 
pd="'2*int((nf+1)/2) * (W/nf + 0.29)'"
as="'int((nf+2)/2) * W/nf * 0.29'" 
ps="'2*int((nf+2)/2) * (W/nf + 0.29)'"
nrd="'0.29 / W'" nrs="'0.29 / W'"
sa=0 sb=0 sd=0
model=nfet_01v8
spiceprefix=X
}
C {madvlsi/nmos3.sym} 520 540 3 0 {name=M46
L=0.5
W=4
body=GND
nf=1
mult=1
ad="'int((nf+1)/2) * W/nf * 0.29'" 
pd="'2*int((nf+1)/2) * (W/nf + 0.29)'"
as="'int((nf+2)/2) * W/nf * 0.29'" 
ps="'2*int((nf+2)/2) * (W/nf + 0.29)'"
nrd="'0.29 / W'" nrs="'0.29 / W'"
sa=0 sb=0 sd=0
model=nfet_01v8
spiceprefix=X
}
C {madvlsi/nmos3.sym} 600 540 3 0 {name=M47
L=0.5
W=4
body=GND
nf=1
mult=1
ad="'int((nf+1)/2) * W/nf * 0.29'" 
pd="'2*int((nf+1)/2) * (W/nf + 0.29)'"
as="'int((nf+2)/2) * W/nf * 0.29'" 
ps="'2*int((nf+2)/2) * (W/nf + 0.29)'"
nrd="'0.29 / W'" nrs="'0.29 / W'"
sa=0 sb=0 sd=0
model=nfet_01v8
spiceprefix=X
}
C {madvlsi/nmos3.sym} 680 540 3 0 {name=M48
L=0.5
W=4
body=GND
nf=1
mult=1
ad="'int((nf+1)/2) * W/nf * 0.29'" 
pd="'2*int((nf+1)/2) * (W/nf + 0.29)'"
as="'int((nf+2)/2) * W/nf * 0.29'" 
ps="'2*int((nf+2)/2) * (W/nf + 0.29)'"
nrd="'0.29 / W'" nrs="'0.29 / W'"
sa=0 sb=0 sd=0
model=nfet_01v8
spiceprefix=X
}
C {madvlsi/nmos3.sym} 240 540 1 0 {name=M49
L=0.5
W=4
body=GND
nf=1
mult=1
ad="'int((nf+1)/2) * W/nf * 0.29'" 
pd="'2*int((nf+1)/2) * (W/nf + 0.29)'"
as="'int((nf+2)/2) * W/nf * 0.29'" 
ps="'2*int((nf+2)/2) * (W/nf + 0.29)'"
nrd="'0.29 / W'" nrs="'0.29 / W'"
sa=0 sb=0 sd=0
model=nfet_01v8
spiceprefix=X
}
C {madvlsi/nmos3.sym} 320 540 1 0 {name=M50
L=0.5
W=4
body=GND
nf=1
mult=1
ad="'int((nf+1)/2) * W/nf * 0.29'" 
pd="'2*int((nf+1)/2) * (W/nf + 0.29)'"
as="'int((nf+2)/2) * W/nf * 0.29'" 
ps="'2*int((nf+2)/2) * (W/nf + 0.29)'"
nrd="'0.29 / W'" nrs="'0.29 / W'"
sa=0 sb=0 sd=0
model=nfet_01v8
spiceprefix=X
}
C {madvlsi/nmos3.sym} 400 540 1 0 {name=M51
L=0.5
W=4
body=GND
nf=1
mult=1
ad="'int((nf+1)/2) * W/nf * 0.29'" 
pd="'2*int((nf+1)/2) * (W/nf + 0.29)'"
as="'int((nf+2)/2) * W/nf * 0.29'" 
ps="'2*int((nf+2)/2) * (W/nf + 0.29)'"
nrd="'0.29 / W'" nrs="'0.29 / W'"
sa=0 sb=0 sd=0
model=nfet_01v8
spiceprefix=X
}
C {madvlsi/nmos3.sym} 1080 540 1 0 {name=M52
L=0.5
W=4
body=GND
nf=1
mult=1
ad="'int((nf+1)/2) * W/nf * 0.29'" 
pd="'2*int((nf+1)/2) * (W/nf + 0.29)'"
as="'int((nf+2)/2) * W/nf * 0.29'" 
ps="'2*int((nf+2)/2) * (W/nf + 0.29)'"
nrd="'0.29 / W'" nrs="'0.29 / W'"
sa=0 sb=0 sd=0
model=nfet_01v8
spiceprefix=X
}
C {madvlsi/nmos3.sym} 1160 540 1 0 {name=M53
L=0.5
W=4
body=GND
nf=1
mult=1
ad="'int((nf+1)/2) * W/nf * 0.29'" 
pd="'2*int((nf+1)/2) * (W/nf + 0.29)'"
as="'int((nf+2)/2) * W/nf * 0.29'" 
ps="'2*int((nf+2)/2) * (W/nf + 0.29)'"
nrd="'0.29 / W'" nrs="'0.29 / W'"
sa=0 sb=0 sd=0
model=nfet_01v8
spiceprefix=X
}
C {madvlsi/nmos3.sym} 1240 540 1 0 {name=M54
L=0.5
W=4
body=GND
nf=1
mult=1
ad="'int((nf+1)/2) * W/nf * 0.29'" 
pd="'2*int((nf+1)/2) * (W/nf + 0.29)'"
as="'int((nf+2)/2) * W/nf * 0.29'" 
ps="'2*int((nf+2)/2) * (W/nf + 0.29)'"
nrd="'0.29 / W'" nrs="'0.29 / W'"
sa=0 sb=0 sd=0
model=nfet_01v8
spiceprefix=X
}
